VERSION 5.7 ;
BUSBITCHARS "[]" ;
DIVIDERCHAR "/" ;

PROPERTYDEFINITIONS
  MACRO CatenaDesignType STRING ;
END PROPERTYDEFINITIONS

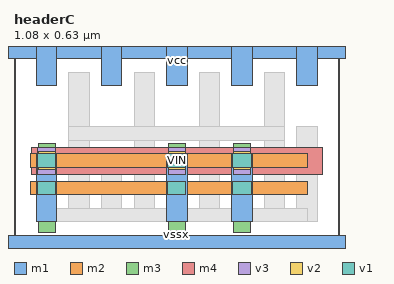
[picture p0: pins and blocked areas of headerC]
MACRO headerC
  CLASS CORE ;
  ORIGIN 0 0 ;
  FOREIGN headerC 0 0 ;
  SIZE 1.08 BY 0.63 ;
  SYMMETRY X Y ;
  SITE CoreSite ;
  PIN VIN
    DIRECTION OUTPUT ;
    USE SIGNAL ;
    PORT
      LAYER m1 ;
        RECT 0.722 0.068 0.79 0.292 ;
        RECT 0.506 0.068 0.574 0.292 ;
        RECT 0.074 0.068 0.142 0.292 ;
      LAYER m2 ;
        RECT 0.056 0.158 0.972 0.202 ;
        RECT 0.056 0.248 0.972 0.292 ;
      LAYER m3 ;
        RECT 0.728 0.033 0.784 0.327 ;
        RECT 0.512 0.033 0.568 0.327 ;
        RECT 0.08 0.033 0.136 0.327 ;
      LAYER m4 ;
        RECT 0.058 0.225 1.022 0.315 ;
      LAYER v3 ;
        RECT 0.079 0.225 0.137 0.315 ;
        RECT 0.511 0.225 0.569 0.315 ;
        RECT 0.727 0.225 0.785 0.315 ;
      LAYER v2 ;
        RECT 0.08 0.241 0.136 0.299 ;
        RECT 0.512 0.241 0.568 0.299 ;
        RECT 0.728 0.241 0.784 0.299 ;
      LAYER v1 ;
        RECT 0.078 0.248 0.138 0.292 ;
        RECT 0.078 0.158 0.138 0.202 ;
        RECT 0.51 0.248 0.57 0.292 ;
        RECT 0.51 0.158 0.57 0.202 ;
        RECT 0.726 0.248 0.786 0.292 ;
        RECT 0.726 0.158 0.786 0.202 ;
    END
  END VIN
  PIN vcc
    DIRECTION INOUT ;
    USE POWER ;
    SHAPE ABUTMENT ;
    PORT
      LAYER m1 ;
        RECT -0.034 0.608 1.114 0.652 ;
        RECT 0.938 0.518 1.006 0.652 ;
        RECT 0.722 0.518 0.79 0.652 ;
        RECT 0.506 0.518 0.574 0.652 ;
        RECT 0.29 0.518 0.358 0.652 ;
        RECT 0.074 0.518 0.142 0.652 ;
    END
  END vcc
  PIN vssx
    DIRECTION INOUT ;
    USE GROUND ;
    SHAPE ABUTMENT ;
    PORT
      LAYER m1 ;
        RECT -0.034 -0.022 1.114 0.022 ;
    END
  END vssx
  OBS
    LAYER m1 ;
      RECT 0.83 0.068 0.898 0.562 ;
      RECT 0.614 0.068 0.682 0.562 ;
      RECT 0.398 0.068 0.466 0.562 ;
      RECT 0.182 0.068 0.25 0.562 ;
      RECT 0.182 0.338 0.898 0.382 ;
      RECT 0.938 0.068 1.006 0.382 ;
      RECT 0.29 0.068 0.358 0.292 ;
    LAYER m2 ;
      RECT 0.108 0.068 0.972 0.112 ;
  END
  PROPERTY CatenaDesignType "deviceLevel" ;
END headerC

END LIBRARY
